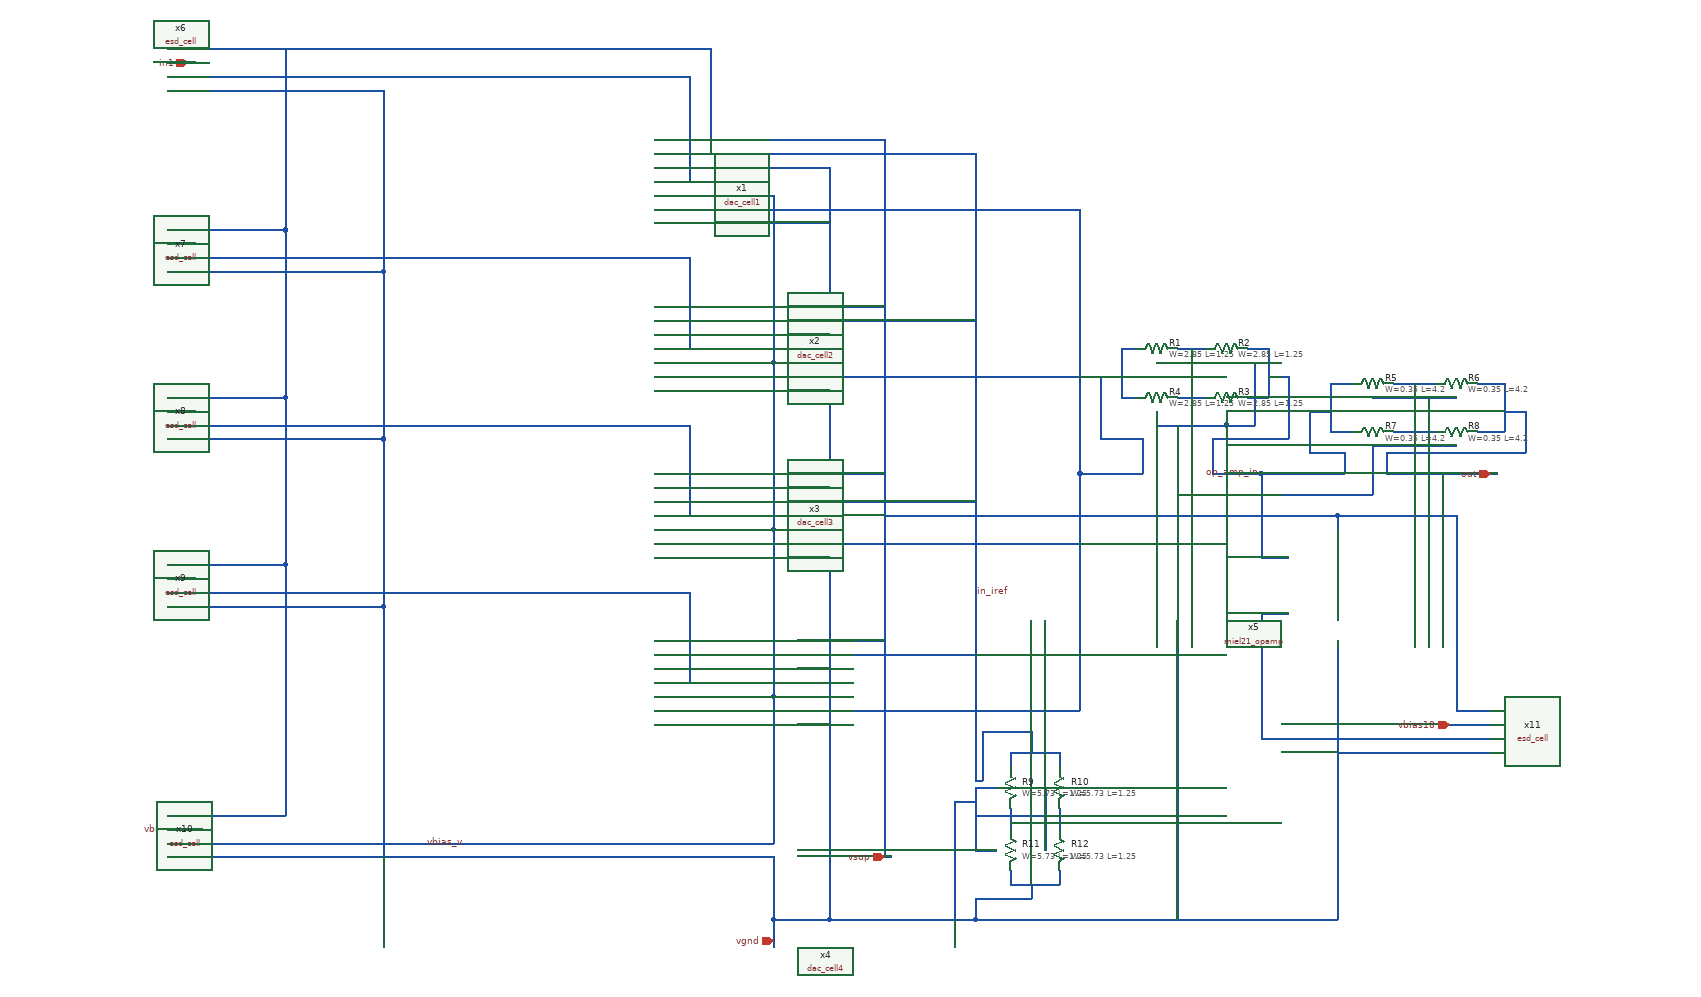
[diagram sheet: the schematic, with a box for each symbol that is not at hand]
v {xschem version=2.9.9 file_version=1.2 }
G {}
K {}
V {}
S {}
E {}
N 1600 -1150 1600 -940 { lab=in_iref}
N 1430 -1150 1600 -1150 { lab=in_iref}
N 1430 -1390 1600 -1390 { lab=in_iref}
N 1600 -1390 1600 -1150 { lab=in_iref}
N 1600 -1630 1600 -1390 { lab=in_iref}
N 1430 -1630 1600 -1630 { lab=in_iref}
N 1600 -1860 1600 -1630 { lab=in_iref}
N 1600 -1870 1600 -1860 { lab=in_iref}
N 1430 -1870 1600 -1870 { lab=in_iref}
N 1600 -830 1680 -830 { lab=vgnd}
N 1680 -1890 1680 -830 { lab=vgnd}
N 1430 -1910 1680 -1910 { lab=vgnd}
N 1680 -1910 1680 -1890 { lab=vgnd}
N 1430 -1670 1680 -1670 { lab=vgnd}
N 1430 -1190 1680 -1190 { lab=vgnd}
N 1680 -830 1760 -830 { lab=vgnd}
N 1760 -1950 1760 -940 { lab=vsup}
N 1430 -1950 1760 -1950 { lab=vsup}
N 1430 -1710 1760 -1710 { lab=vsup}
N 1430 -1470 1760 -1470 { lab=vsup}
N 1430 -1230 1760 -1230 { lab=vsup}
N 1760 -830 1890 -830 { lab=vgnd}
N 1430 -1930 1890 -1930 { lab=in_iref}
N 1430 -1690 1890 -1690 { lab=in_iref}
N 1430 -1210 1890 -1210 { lab=in_iref}
N 2480 -1470 2620 -1470 { lab=out}
N 1480 -2000 1480 -1890 { lab=#net1}
N 1430 -1890 1480 -1890 { lab=#net1}
N 1480 -1760 1480 -1650 { lab=#net2}
N 1430 -1650 1480 -1650 { lab=#net2}
N 1480 -1520 1480 -1410 { lab=#net3}
N 1430 -1410 1480 -1410 { lab=#net3}
N 1480 -1280 1480 -1170 { lab=#net4}
N 1430 -1170 1480 -1170 { lab=#net4}
N 1480 -2040 1480 -2000 { lab=#net1}
N 1030 -2040 1480 -2040 { lab=#net1}
N 1030 -1780 1480 -1780 { lab=#net2}
N 1480 -1780 1480 -1760 { lab=#net2}
N 1030 -1540 1480 -1540 { lab=#net3}
N 1480 -1540 1480 -1520 { lab=#net3}
N 1030 -1300 1480 -1300 { lab=#net4}
N 1480 -1300 1480 -1280 { lab=#net4}
N 2040 -1820 2040 -1470 { lab=#net5}
N 2040 -1470 2040 -1350 { lab=#net5}
N 2410 -1230 2410 -1210 { lab=vgnd}
N 2410 -1210 2410 -1160 { lab=vgnd}
N 2040 -1350 2040 -1130 { lab=#net5}
N 2300 -1470 2340 -1470 { lab=op_amp_in}
N 2400 -1470 2420 -1470 { lab=op_amp_in}
N 2040 -1470 2060 -1470 { lab=#net5}
N 2340 -1470 2400 -1470 { lab=op_amp_in}
N 2560 -1470 2560 -1310 { lab=out}
N 2300 -1350 2340 -1350 { lab=op_amp_in}
N 2300 -1470 2300 -1350 { lab=op_amp_in}
N 2060 -1470 2070 -1470 { lab=#net5}
N 2230 -1470 2300 -1470 { lab=op_amp_in}
N 1890 -1930 1890 -1030 { lab=in_iref}
N 1020 -2040 1030 -2040 { lab=#net1}
N 1010 -1780 1030 -1780 { lab=#net2}
N 1010 -1540 1030 -1540 { lab=#net3}
N 1010 -1300 1030 -1300 { lab=#net4}
N 1570 -940 1600 -940 { lab=in_iref}
N 1600 -810 1600 -790 { lab=vgnd}
N 1600 -830 1600 -810 { lab=vgnd}
N 1760 -940 1760 -920 { lab=vsup}
N 1760 -920 1770 -920 { lab=vsup}
N 2620 -1470 2640 -1470 { lab=out}
N 2410 -1160 2410 -1140 { lab=vgnd}
N 1890 -830 2410 -830 { lab=vgnd}
N 2410 -1140 2410 -830 { lab=vgnd}
N 1760 -1410 2410 -1410 { lab=vsup}
N 2410 -1410 2410 -1390 { lab=vsup}
N 2080 -1470 2130 -1470 { lab=#net5}
N 2070 -1470 2080 -1470 { lab=#net5}
N 1860 -960 1860 -830 { lab=vgnd}
N 2040 -1830 2040 -1820 { lab=#net5}
N 1430 -1130 2040 -1130 { lab=#net5}
N 1430 -1850 2040 -1850 { lab=#net5}
N 2040 -1850 2040 -1830 { lab=#net5}
N 1430 -1610 2040 -1610 { lab=#net5}
N 1430 -1370 2040 -1370 { lab=#net5}
N 2180 -1650 2220 -1650 { lab=#net6}
N 2180 -1580 2220 -1580 { lab=#net6}
N 2280 -1650 2310 -1650 { lab=op_amp_in}
N 2310 -1650 2310 -1580 { lab=op_amp_in}
N 2280 -1580 2310 -1580 { lab=op_amp_in}
N 2100 -1650 2120 -1650 { lab=#net5}
N 2100 -1650 2100 -1580 { lab=#net5}
N 2100 -1580 2120 -1580 { lab=#net5}
N 2310 -1610 2340 -1610 { lab=op_amp_in}
N 2070 -1610 2100 -1610 { lab=#net5}
N 2200 -1650 2200 -1580 { lab=#net6}
N 2130 -1520 2130 -1470 { lab=#net5}
N 2070 -1520 2130 -1520 { lab=#net5}
N 2070 -1610 2070 -1520 { lab=#net5}
N 2230 -1520 2230 -1470 { lab=op_amp_in}
N 2230 -1520 2340 -1520 { lab=op_amp_in}
N 2340 -1610 2340 -1520 { lab=op_amp_in}
N 2150 -1630 2250 -1630 { lab=vgnd}
N 2150 -1560 2150 -1540 { lab=vgnd}
N 2150 -1540 2250 -1540 { lab=vgnd}
N 2250 -1560 2250 -1540 { lab=vgnd}
N 2180 -1540 2180 -830 { lab=vgnd}
N 2400 -1600 2430 -1600 { lab=op_amp_in}
N 2400 -1600 2400 -1530 { lab=op_amp_in}
N 2400 -1530 2430 -1530 { lab=op_amp_in}
N 2490 -1530 2550 -1530 { lab=#net7}
N 2490 -1600 2550 -1600 { lab=#net7}
N 2610 -1600 2650 -1600 { lab=out}
N 2650 -1600 2650 -1530 { lab=out}
N 2610 -1530 2650 -1530 { lab=out}
N 2370 -1560 2400 -1560 { lab=op_amp_in}
N 2650 -1560 2680 -1560 { lab=out}
N 2520 -1600 2520 -1530 { lab=#net7}
N 2420 -1500 2420 -1470 { lab=op_amp_in}
N 2370 -1500 2420 -1500 { lab=op_amp_in}
N 2370 -1560 2370 -1500 { lab=op_amp_in}
N 2480 -1500 2480 -1470 { lab=out}
N 2480 -1500 2680 -1500 { lab=out}
N 2680 -1560 2680 -1500 { lab=out}
N 2460 -1510 2580 -1510 { lab=vgnd}
N 2460 -1580 2580 -1580 { lab=vgnd}
N 2540 -1580 2540 -1510 { lab=vgnd}
N 2460 -1510 2460 -1440 { lab=vgnd}
N 2180 -1440 2460 -1440 { lab=vgnd}
N 1940 -1070 1940 -1050 { lab=in_iref}
N 1940 -1070 2010 -1070 { lab=in_iref}
N 2010 -1070 2010 -1050 { lab=in_iref}
N 1940 -900 1940 -880 { lab=vgnd}
N 1940 -880 2010 -880 { lab=vgnd}
N 2010 -900 2010 -880 { lab=vgnd}
N 1940 -990 1940 -960 { lab=#net8}
N 2010 -990 2010 -960 { lab=#net8}
N 1970 -1100 1970 -1070 { lab=in_iref}
N 1970 -880 1970 -860 { lab=vgnd}
N 1940 -970 2010 -970 { lab=#net8}
N 1890 -1030 1900 -1030 { lab=in_iref}
N 1900 -1100 1900 -1030 { lab=in_iref}
N 1900 -1100 1970 -1100 { lab=in_iref}
N 1900 -860 1970 -860 { lab=vgnd}
N 1890 -860 1900 -860 { lab=vgnd}
N 1890 -860 1890 -830 { lab=vgnd}
N 1990 -1020 1990 -930 { lab=vgnd}
N 1890 -1020 1920 -1020 { lab=vgnd}
N 1890 -1020 1890 -930 { lab=vgnd}
N 1890 -930 1920 -930 { lab=vgnd}
N 1890 -980 1990 -980 { lab=vgnd}
N 1890 -1000 1890 -980 { lab=vgnd}
N 1860 -1000 1890 -1000 { lab=vgnd}
N 1860 -1000 1860 -960 { lab=vgnd}
N 1430 -1830 1680 -1830 { lab=vgnd}
N 1430 -1590 1680 -1590 { lab=vgnd}
N 1430 -1350 1680 -1350 { lab=vgnd}
N 1430 -1110 1680 -1110 { lab=vgnd}
N 2250 -1630 2290 -1630 { lab=vgnd}
N 2290 -1630 2290 -1540 { lab=vgnd}
N 2250 -1540 2290 -1540 { lab=vgnd}
N 1430 -1430 1890 -1430 { lab=in_iref}
N 1430 -1450 1680 -1450 { lab=vgnd}
N 730 -2080 770 -2080 { lab=vsup}
N 730 -2060 770 -2060 { lab=in1}
N 730 -2040 1020 -2040 { lab=#net1}
N 730 -2020 770 -2020 { lab=vgnd}
N 730 -1780 1010 -1780 { lab=#net2}
N 730 -1800 770 -1800 { lab=in2}
N 730 -1820 770 -1820 { lab=vsup}
N 730 -1760 770 -1760 { lab=vgnd}
N 730 -1540 1010 -1540 { lab=#net3}
N 730 -1580 770 -1580 { lab=vsup}
N 730 -1560 770 -1560 { lab=in3}
N 730 -1520 770 -1520 { lab=vgnd}
N 730 -1300 1010 -1300 { lab=#net4}
N 730 -1340 770 -1340 { lab=vsup}
N 730 -1320 770 -1320 { lab=in4}
N 730 -1280 770 -1280 { lab=vgnd}
N 920 -940 1570 -940 { lab=in_iref}
N 730 -940 920 -940 { lab=in_iref}
N 730 -960 780 -960 { lab=vbias07}
N 730 -920 780 -920 { lab=vgnd}
N 2560 -1110 2630 -1110 { lab=vbias18}
N 2300 -1270 2340 -1270 { lab=#net9}
N 2300 -1270 2300 -1100 { lab=#net9}
N 2300 -1100 2300 -1090 { lab=#net9}
N 2300 -1090 2630 -1090 { lab=#net9}
N 2560 -1070 2630 -1070 { lab=vgnd}
N 770 -2080 1510 -2080 { lab=vsup}
N 1510 -2080 1510 -1950 { lab=vsup}
N 770 -1820 900 -1820 { lab=vsup}
N 900 -2080 900 -1820 { lab=vsup}
N 730 -980 770 -980 { lab=vsup}
N 780 -920 1590 -920 { lab=vgnd}
N 1590 -920 1600 -920 { lab=vgnd}
N 1600 -920 1600 -830 { lab=vgnd}
N 770 -1280 1040 -1280 { lab=vgnd}
N 1040 -1280 1040 -920 { lab=vgnd}
N 770 -1520 1040 -1520 { lab=vgnd}
N 1040 -1520 1040 -1280 { lab=vgnd}
N 770 -1760 1030 -1760 { lab=vgnd}
N 1030 -1760 1040 -1760 { lab=vgnd}
N 1040 -1760 1040 -1520 { lab=vgnd}
N 770 -2020 1040 -2020 { lab=vgnd}
N 1040 -2020 1040 -1760 { lab=vgnd}
N 770 -1580 900 -1580 { lab=vsup}
N 900 -1820 900 -1580 { lab=vsup}
N 770 -1340 900 -1340 { lab=vsup}
N 900 -1580 900 -1340 { lab=vsup}
N 770 -980 890 -980 { lab=vsup}
N 890 -980 900 -980 { lab=vsup}
N 900 -1340 900 -980 { lab=vsup}
N 2410 -1070 2560 -1070 { lab=vgnd}
N 2410 -1410 2580 -1410 { lab=vsup}
N 2580 -1410 2580 -1130 { lab=vsup}
N 2580 -1130 2630 -1130 { lab=vsup}
C {/opt/uniccass/dev/dac_cell2/tb/dac_cell2.sym} 1280 -1650 0 0 {name=x2}
C {/opt/uniccass/dev/dac_cell3/tb/dac_cell3.sym} 1280 -1410 0 0 {name=x3}
C {/opt/uniccass/dev/dac_cell4/tb/dac_cell4.sym} 1280 -1170 0 0 {name=x4}
C {devices/lab_wire.sym} 2300 -1470 1 0 {name=l2 sig_type=std_logic lab=op_amp_in}
C {/opt/uniccass/dev/opamp/miel21_opamp.sym} 2490 -1310 0 0 {name=x5}
C {devices/iopin.sym} 760 -2060 0 0 {name=p1 lab=in1}
C {devices/iopin.sym} 760 -1800 0 0 {name=p2 lab=in2}
C {devices/iopin.sym} 760 -1560 0 0 {name=p3 lab=in3}
C {devices/iopin.sym} 760 -1320 0 0 {name=p4 lab=in4}
C {devices/iopin.sym} 770 -960 0 0 {name=p5 lab=vbias07}
C {devices/iopin.sym} 1600 -800 1 0 {name=p6 lab=vgnd}
C {devices/iopin.sym} 1760 -920 0 0 {name=p7 lab=vsup}
C {devices/iopin.sym} 2630 -1470 0 0 {name=p9 lab=out}
C {devices/iopin.sym} 2570 -1110 2 0 {name=p11 lab=vbias18}
C {/opt/uniccass/dev/dac_cell1/tb/dac_cell1.sym} 1280 -1890 0 0 {name=x1}
C {sky130_fd_pr/res_xhigh_po_2p85.sym} 2150 -1650 3 0 {name=R1
W=2.85
L=1.25
model=res_xhigh_po_2p85
spiceprefix=X
mult=1}
C {sky130_fd_pr/res_xhigh_po_2p85.sym} 2250 -1650 3 0 {name=R2
W=2.85
L=1.25
model=res_xhigh_po_2p85
spiceprefix=X
mult=1}
C {sky130_fd_pr/res_xhigh_po_2p85.sym} 2150 -1580 3 0 {name=R4
W=2.85
L=1.25
model=res_xhigh_po_2p85
spiceprefix=X
mult=1}
C {sky130_fd_pr/res_xhigh_po_2p85.sym} 2250 -1580 3 0 {name=R3
W=2.85
L=1.25
model=res_xhigh_po_2p85
spiceprefix=X
mult=1}
C {sky130_fd_pr/res_xhigh_po_0p35.sym} 2460 -1600 3 0 {name=R5
W=0.35
L=4.2
model=res_xhigh_po_0p35
spiceprefix=X
mult=1}
C {sky130_fd_pr/res_xhigh_po_0p35.sym} 2580 -1600 3 0 {name=R6
W=0.35
L=4.2
model=res_xhigh_po_0p35
spiceprefix=X
mult=1}
C {sky130_fd_pr/res_xhigh_po_0p35.sym} 2460 -1530 3 0 {name=R7
W=0.35
L=4.2
model=res_xhigh_po_0p35
spiceprefix=X
mult=1}
C {sky130_fd_pr/res_xhigh_po_0p35.sym} 2580 -1530 3 0 {name=R8
W=0.35
L=4.2
model=res_xhigh_po_0p35
spiceprefix=X
mult=1}
C {sky130_fd_pr/res_high_po_5p73.sym} 1940 -1020 0 0 {name=R9
W=5.73
L=1.25
model=res_high_po_5p73
spiceprefix=X
mult=1}
C {sky130_fd_pr/res_high_po_5p73.sym} 2010 -1020 0 0 {name=R10
W=5.73
L=1.25
model=res_high_po_5p73
spiceprefix=X
mult=1}
C {sky130_fd_pr/res_high_po_5p73.sym} 1940 -930 0 0 {name=R11
W=5.73
L=1.25
model=res_high_po_5p73
spiceprefix=X
mult=1}
C {sky130_fd_pr/res_high_po_5p73.sym} 2010 -930 0 0 {name=R12
W=5.73
L=1.25
model=res_high_po_5p73
spiceprefix=X
mult=1}
C {devices/lab_wire.sym} 1890 -1300 2 0 {name=l1 sig_type=std_logic lab=in_iref}
C {/opt/uniccass/dev/esd_cell/tb/esd_cell.sym} 580 -2050 0 0 {name=x6}
C {/opt/uniccass/dev/esd_cell/tb/esd_cell.sym} 580 -1790 0 0 {name=x7}
C {/opt/uniccass/dev/esd_cell/tb/esd_cell.sym} 580 -1550 0 0 {name=x8}
C {/opt/uniccass/dev/esd_cell/tb/esd_cell.sym} 580 -1310 0 0 {name=x9}
C {/opt/uniccass/dev/esd_cell/tb/esd_cell.sym} 580 -950 0 0 {name=x10}
C {/opt/uniccass/dev/esd_cell/tb/esd_cell.sym} 2780 -1100 0 1 {name=x11}
C {devices/lab_wire.sym} 1100 -940 2 0 {name=l3 sig_type=std_logic lab=vbias_v}
